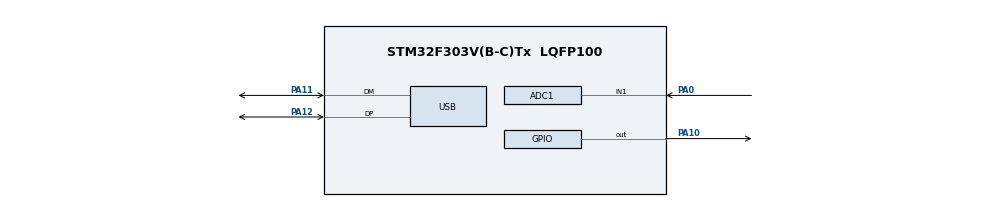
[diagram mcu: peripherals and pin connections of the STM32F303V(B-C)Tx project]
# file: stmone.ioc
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ADC1.Channel-1\#ChannelRegularConversion=ADC_CHANNEL_1
ADC1.NbrOfConversionFlag=1
ADC1.Offset-1\#ChannelRegularConversion=0
ADC1.OffsetNumber-1\#ChannelRegularConversion=ADC_OFFSET_NONE
ADC1.Rank-1\#ChannelRegularConversion=1
ADC1.SamplingTime-1\#ChannelRegularConversion=ADC_SAMPLETIME_1CYCLE_5
ADC1.SamplingTimeOPAMP-1\#ChannelRegularConversion=ADC_SAMPLETIME_61CYCLES_5
ADC1.master=1
Mcu.Family=STM32F3
Mcu.Name=STM32F303V(B-C)Tx
Mcu.Package=LQFP100
NVIC.PriorityGroup=NVIC_PRIORITYGROUP_4
PA0.Mode=IN1-Single-Ended
PA0.Signal=ADC1_IN1
PA10.Signal=GPIO_Output
PA11.Mode=Device
PA11.Signal=USB_DM
PA12.Mode=Device
PA12.Signal=USB_DP
PA13.Mode=Serial_Wire
PA13.Signal=SYS_JTMS-SWDIO
PA14.Mode=Serial_Wire
PA14.Signal=SYS_JTCK-SWCLK
ProjectManager.HeapSize=0x200
ProjectManager.StackSize=0x400
ProjectManager.TargetToolchain=Makefile
RCC.AHBFreq_Value=48000000
RCC.APB1CLKDivider=RCC_HCLK_DIV2
RCC.APB1Freq_Value=24000000
RCC.APB1TimFreq_Value=48000000
RCC.APB2Freq_Value=48000000
RCC.APB2TimFreq_Value=48000000
RCC.CortexFreq_Value=48000000
RCC.HCLKFreq_Value=48000000
RCC.HSE_VALUE=8000000
RCC.HSI_VALUE=8000000
RCC.LSE_VALUE=32768
RCC.PLLMUL=RCC_PLL_MUL12
RCC.PLLSourceVirtualString=RCC_PLLSOURCE_HSI
RCC.SYSCLKFreq_VALUE=48000000
RCC.SYSCLKSourceVirtual=RCC_SYSCLKSOURCE_PLLCLK
RCC.USBFreq_Value=48000000
board=custom

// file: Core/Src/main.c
/* USER CODE BEGIN Header */
/**
  ******************************************************************************
  * @file           : main.c
  * @brief          : Main program body
  ******************************************************************************
  * @attention
  *
  * Copyright (c) 2023 STMicroelectronics.
  * All rights reserved.
  *
  * This software is licensed under terms that can be found in the LICENSE file
  * in the root directory of this software component.
  * If no LICENSE file comes with this software, it is provided AS-IS.
  *
  ******************************************************************************
  */
/* USER CODE END Header */
#include "main.h"

ADC_HandleTypeDef hadc1;

void SystemClock_Config(void);
static void MX_GPIO_Init(void);
static void MX_ADC1_Init(void);

int main(void)
{
  /* USER CODE BEGIN 1 */
  uint16_t raw;
  char msg[10];

  /* USER CODE END 1 */

  /* MCU Configuration--------------------------------------------------------*/

  /* Reset of all peripherals, Initializes the Flash interface and the Systick. */
  HAL_Init();

  /* Configure the system clock */
  SystemClock_Config();

  /* Initialize all configured peripherals */
  MX_GPIO_Init();
  MX_ADC1_Init();

  /* Infinite loop */
  /* USER CODE BEGIN WHILE */
  while (1)
  {
    HAL_GPIO_WritePin(GPIOA, GPIO_PIN_10, GPIO_PIN_SET);
    HAL_ADC_Start(&hadc1);
    HAL_ADC_PollForConversion(&hadc1, HAL_MAX_DELAY);
    raw = HAL_ADC_GetValue(&hadc1);

    sprintf(msg, "%hu\n", raw);

    /* HAL_UART_Transmit(&huart */
    /* USER CODE END WHILE */

  }
}

void SystemClock_Config(void)
{
  RCC_OscInitTypeDef RCC_OscInitStruct = {0};
  RCC_ClkInitTypeDef RCC_ClkInitStruct = {0};
  RCC_PeriphCLKInitTypeDef PeriphClkInit = {0};

  /** Initializes the RCC Oscillators according to the specified parameters
  * in the RCC_OscInitTypeDef structure.
  */
  RCC_OscInitStruct.OscillatorType = RCC_OSCILLATORTYPE_HSI;
  RCC_OscInitStruct.HSIState = RCC_HSI_ON;
  RCC_OscInitStruct.HSICalibrationValue = RCC_HSICALIBRATION_DEFAULT;
  RCC_OscInitStruct.PLL.PLLState = RCC_PLL_ON;
  RCC_OscInitStruct.PLL.PLLSource = RCC_PLLSOURCE_HSI;
  RCC_OscInitStruct.PLL.PLLMUL = RCC_PLL_MUL16;
  if (HAL_RCC_OscConfig(&RCC_OscInitStruct) != HAL_OK)
  {
    Error_Handler();
  }

  /** Initializes the CPU, AHB and APB buses clocks
  */
  RCC_ClkInitStruct.ClockType = RCC_CLOCKTYPE_HCLK|RCC_CLOCKTYPE_SYSCLK
                              |RCC_CLOCKTYPE_PCLK1|RCC_CLOCKTYPE_PCLK2;
  RCC_ClkInitStruct.SYSCLKSource = RCC_SYSCLKSOURCE_PLLCLK;
  RCC_ClkInitStruct.AHBCLKDivider = RCC_SYSCLK_DIV1;
  RCC_ClkInitStruct.APB1CLKDivider = RCC_HCLK_DIV2;
  RCC_ClkInitStruct.APB2CLKDivider = RCC_HCLK_DIV1;

  if (HAL_RCC_ClockConfig(&RCC_ClkInitStruct, FLASH_LATENCY_2) != HAL_OK)
  {
    Error_Handler();
  }
  PeriphClkInit.PeriphClockSelection = RCC_PERIPHCLK_ADC12;
  PeriphClkInit.Adc12ClockSelection = RCC_ADC12PLLCLK_DIV1;
  if (HAL_RCCEx_PeriphCLKConfig(&PeriphClkInit) != HAL_OK)
  {
    Error_Handler();
  }
}

static void MX_ADC1_Init(void)
{

  ADC_MultiModeTypeDef multimode = {0};
  ADC_ChannelConfTypeDef sConfig = {0};

  /** Common config
  */
  hadc1.Instance = ADC1;
  hadc1.Init.ClockPrescaler = ADC_CLOCK_ASYNC_DIV1;
  hadc1.Init.Resolution = ADC_RESOLUTION_12B;
  hadc1.Init.ScanConvMode = ADC_SCAN_DISABLE;
  hadc1.Init.ContinuousConvMode = DISABLE;
  hadc1.Init.DiscontinuousConvMode = DISABLE;
  hadc1.Init.ExternalTrigConvEdge = ADC_EXTERNALTRIGCONVEDGE_NONE;
  hadc1.Init.ExternalTrigConv = ADC_SOFTWARE_START;
  hadc1.Init.DataAlign = ADC_DATAALIGN_RIGHT;
  hadc1.Init.NbrOfConversion = 1;
  hadc1.Init.DMAContinuousRequests = DISABLE;
  hadc1.Init.EOCSelection = ADC_EOC_SINGLE_CONV;
  hadc1.Init.LowPowerAutoWait = DISABLE;
  hadc1.Init.Overrun = ADC_OVR_DATA_OVERWRITTEN;
  if (HAL_ADC_Init(&hadc1) != HAL_OK)
  {
    Error_Handler();
  }

  /** Configure the ADC multi-mode
  */
  multimode.Mode = ADC_MODE_INDEPENDENT;
  if (HAL_ADCEx_MultiModeConfigChannel(&hadc1, &multimode) != HAL_OK)
  {
    Error_Handler();
  }

  /** Configure Regular Channel
  */
  sConfig.Channel = ADC_CHANNEL_1;
  sConfig.Rank = ADC_REGULAR_RANK_1;
  sConfig.SingleDiff = ADC_SINGLE_ENDED;
  sConfig.SamplingTime = ADC_SAMPLETIME_1CYCLE_5;
  sConfig.OffsetNumber = ADC_OFFSET_NONE;
  sConfig.Offset = 0;
  if (HAL_ADC_ConfigChannel(&hadc1, &sConfig) != HAL_OK)
  {
    Error_Handler();
  }

}

static void MX_GPIO_Init(void)
{
  GPIO_InitTypeDef GPIO_InitStruct = {0};

  /* GPIO Ports Clock Enable */
  __HAL_RCC_GPIOA_CLK_ENABLE();

  /*Configure GPIO pin Output Level */
  HAL_GPIO_WritePin(GPIOA, GPIO_PIN_10, GPIO_PIN_RESET);

  /*Configure GPIO pin : PA10 */
  GPIO_InitStruct.Pin = GPIO_PIN_10;
  GPIO_InitStruct.Mode = GPIO_MODE_OUTPUT_PP;
  GPIO_InitStruct.Pull = GPIO_NOPULL;
  GPIO_InitStruct.Speed = GPIO_SPEED_FREQ_LOW;
  HAL_GPIO_Init(GPIOA, &GPIO_InitStruct);

}

void Error_Handler(void)
{
  __disable_irq();
  while (1)
  {
  }
}
